VERSION 5.8 ;
BUSBITCHARS "[]" ;
DIVIDERCHAR "/" ;
UNITS
    DATABASE MICRONS 1000 ;
END UNITS

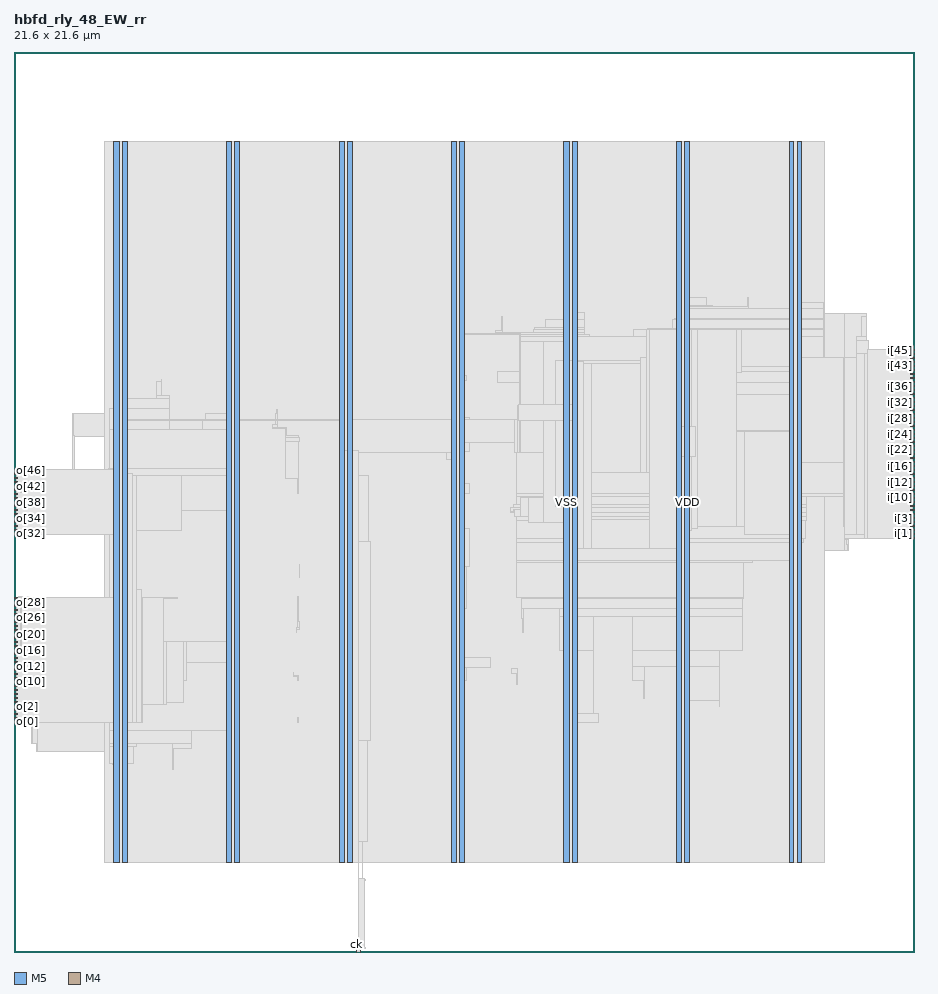
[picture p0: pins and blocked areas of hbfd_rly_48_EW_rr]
MACRO hbfd_rly_48_EW_rr
  FOREIGN hbfd_rly_48_EW_rr 0 0 ;
  CLASS BLOCK ;
  SIZE 21.6 BY 21.6 ;
  PIN ck
    DIRECTION INPUT ;
    USE SIGNAL ;
    PORT
      LAYER M5 ;
        RECT  8.208 0 8.232 0.084 ;
    END
  END ck
  PIN i[0]
    DIRECTION INPUT ;
    USE SIGNAL ;
    PORT
      LAYER M4 ;
        RECT  21.516 9.936 21.6 9.96 ;
    END
  END i[0]
  PIN i[10]
    DIRECTION INPUT ;
    USE SIGNAL ;
    PORT
      LAYER M4 ;
        RECT  21.516 10.896 21.6 10.92 ;
    END
  END i[10]
  PIN i[11]
    DIRECTION INPUT ;
    USE SIGNAL ;
    PORT
      LAYER M4 ;
        RECT  21.516 10.992 21.6 11.016 ;
    END
  END i[11]
  PIN i[12]
    DIRECTION INPUT ;
    USE SIGNAL ;
    PORT
      LAYER M4 ;
        RECT  21.516 11.088 21.6 11.112 ;
    END
  END i[12]
  PIN i[13]
    DIRECTION INPUT ;
    USE SIGNAL ;
    PORT
      LAYER M4 ;
        RECT  21.516 11.184 21.6 11.208 ;
    END
  END i[13]
  PIN i[14]
    DIRECTION INPUT ;
    USE SIGNAL ;
    PORT
      LAYER M4 ;
        RECT  21.516 11.28 21.6 11.304 ;
    END
  END i[14]
  PIN i[15]
    DIRECTION INPUT ;
    USE SIGNAL ;
    PORT
      LAYER M4 ;
        RECT  21.516 11.376 21.6 11.4 ;
    END
  END i[15]
  PIN i[16]
    DIRECTION INPUT ;
    USE SIGNAL ;
    PORT
      LAYER M4 ;
        RECT  21.516 11.472 21.6 11.496 ;
    END
  END i[16]
  PIN i[17]
    DIRECTION INPUT ;
    USE SIGNAL ;
    PORT
      LAYER M4 ;
        RECT  21.516 11.568 21.6 11.592 ;
    END
  END i[17]
  PIN i[18]
    DIRECTION INPUT ;
    USE SIGNAL ;
    PORT
      LAYER M4 ;
        RECT  21.516 11.664 21.6 11.688 ;
    END
  END i[18]
  PIN i[19]
    DIRECTION INPUT ;
    USE SIGNAL ;
    PORT
      LAYER M4 ;
        RECT  21.516 11.76 21.6 11.784 ;
    END
  END i[19]
  PIN i[1]
    DIRECTION INPUT ;
    USE SIGNAL ;
    PORT
      LAYER M4 ;
        RECT  21.516 10.032 21.6 10.056 ;
    END
  END i[1]
  PIN i[20]
    DIRECTION INPUT ;
    USE SIGNAL ;
    PORT
      LAYER M4 ;
        RECT  21.516 11.856 21.6 11.88 ;
    END
  END i[20]
  PIN i[21]
    DIRECTION INPUT ;
    USE SIGNAL ;
    PORT
      LAYER M4 ;
        RECT  21.516 11.952 21.6 11.976 ;
    END
  END i[21]
  PIN i[22]
    DIRECTION INPUT ;
    USE SIGNAL ;
    PORT
      LAYER M4 ;
        RECT  21.516 12.048 21.6 12.072 ;
    END
  END i[22]
  PIN i[23]
    DIRECTION INPUT ;
    USE SIGNAL ;
    PORT
      LAYER M4 ;
        RECT  21.516 12.144 21.6 12.168 ;
    END
  END i[23]
  PIN i[24]
    DIRECTION INPUT ;
    USE SIGNAL ;
    PORT
      LAYER M4 ;
        RECT  21.516 12.24 21.6 12.264 ;
    END
  END i[24]
  PIN i[25]
    DIRECTION INPUT ;
    USE SIGNAL ;
    PORT
      LAYER M4 ;
        RECT  21.516 12.336 21.6 12.36 ;
    END
  END i[25]
  PIN i[26]
    DIRECTION INPUT ;
    USE SIGNAL ;
    PORT
      LAYER M4 ;
        RECT  21.516 12.432 21.6 12.456 ;
    END
  END i[26]
  PIN i[27]
    DIRECTION INPUT ;
    USE SIGNAL ;
    PORT
      LAYER M4 ;
        RECT  21.516 12.528 21.6 12.552 ;
    END
  END i[27]
  PIN i[28]
    DIRECTION INPUT ;
    USE SIGNAL ;
    PORT
      LAYER M4 ;
        RECT  21.516 12.624 21.6 12.648 ;
    END
  END i[28]
  PIN i[29]
    DIRECTION INPUT ;
    USE SIGNAL ;
    PORT
      LAYER M4 ;
        RECT  21.516 12.72 21.6 12.744 ;
    END
  END i[29]
  PIN i[2]
    DIRECTION INPUT ;
    USE SIGNAL ;
    PORT
      LAYER M4 ;
        RECT  21.516 10.128 21.6 10.152 ;
    END
  END i[2]
  PIN i[30]
    DIRECTION INPUT ;
    USE SIGNAL ;
    PORT
      LAYER M4 ;
        RECT  21.516 12.816 21.6 12.84 ;
    END
  END i[30]
  PIN i[31]
    DIRECTION INPUT ;
    USE SIGNAL ;
    PORT
      LAYER M4 ;
        RECT  21.516 12.912 21.6 12.936 ;
    END
  END i[31]
  PIN i[32]
    DIRECTION INPUT ;
    USE SIGNAL ;
    PORT
      LAYER M4 ;
        RECT  21.516 13.008 21.6 13.032 ;
    END
  END i[32]
  PIN i[33]
    DIRECTION INPUT ;
    USE SIGNAL ;
    PORT
      LAYER M4 ;
        RECT  21.516 13.104 21.6 13.128 ;
    END
  END i[33]
  PIN i[34]
    DIRECTION INPUT ;
    USE SIGNAL ;
    PORT
      LAYER M4 ;
        RECT  21.516 13.2 21.6 13.224 ;
    END
  END i[34]
  PIN i[35]
    DIRECTION INPUT ;
    USE SIGNAL ;
    PORT
      LAYER M4 ;
        RECT  21.516 13.296 21.6 13.32 ;
    END
  END i[35]
  PIN i[36]
    DIRECTION INPUT ;
    USE SIGNAL ;
    PORT
      LAYER M4 ;
        RECT  21.516 13.392 21.6 13.416 ;
    END
  END i[36]
  PIN i[37]
    DIRECTION INPUT ;
    USE SIGNAL ;
    PORT
      LAYER M4 ;
        RECT  21.516 13.488 21.6 13.512 ;
    END
  END i[37]
  PIN i[38]
    DIRECTION INPUT ;
    USE SIGNAL ;
    PORT
      LAYER M4 ;
        RECT  21.516 13.584 21.6 13.608 ;
    END
  END i[38]
  PIN i[39]
    DIRECTION INPUT ;
    USE SIGNAL ;
    PORT
      LAYER M4 ;
        RECT  21.516 13.68 21.6 13.704 ;
    END
  END i[39]
  PIN i[3]
    DIRECTION INPUT ;
    USE SIGNAL ;
    PORT
      LAYER M4 ;
        RECT  21.516 10.224 21.6 10.248 ;
    END
  END i[3]
  PIN i[40]
    DIRECTION INPUT ;
    USE SIGNAL ;
    PORT
      LAYER M4 ;
        RECT  21.516 13.776 21.6 13.8 ;
    END
  END i[40]
  PIN i[41]
    DIRECTION INPUT ;
    USE SIGNAL ;
    PORT
      LAYER M4 ;
        RECT  21.516 13.872 21.6 13.896 ;
    END
  END i[41]
  PIN i[42]
    DIRECTION INPUT ;
    USE SIGNAL ;
    PORT
      LAYER M4 ;
        RECT  21.516 13.968 21.6 13.992 ;
    END
  END i[42]
  PIN i[43]
    DIRECTION INPUT ;
    USE SIGNAL ;
    PORT
      LAYER M4 ;
        RECT  21.516 14.064 21.6 14.088 ;
    END
  END i[43]
  PIN i[44]
    DIRECTION INPUT ;
    USE SIGNAL ;
    PORT
      LAYER M4 ;
        RECT  21.516 14.16 21.6 14.184 ;
    END
  END i[44]
  PIN i[45]
    DIRECTION INPUT ;
    USE SIGNAL ;
    PORT
      LAYER M4 ;
        RECT  21.516 14.256 21.6 14.28 ;
    END
  END i[45]
  PIN i[46]
    DIRECTION INPUT ;
    USE SIGNAL ;
    PORT
      LAYER M4 ;
        RECT  21.516 14.352 21.6 14.376 ;
    END
  END i[46]
  PIN i[47]
    DIRECTION INPUT ;
    USE SIGNAL ;
    PORT
      LAYER M4 ;
        RECT  21.516 14.448 21.6 14.472 ;
    END
  END i[47]
  PIN i[4]
    DIRECTION INPUT ;
    USE SIGNAL ;
    PORT
      LAYER M4 ;
        RECT  21.516 10.32 21.6 10.344 ;
    END
  END i[4]
  PIN i[5]
    DIRECTION INPUT ;
    USE SIGNAL ;
    PORT
      LAYER M4 ;
        RECT  21.516 10.416 21.6 10.44 ;
    END
  END i[5]
  PIN i[6]
    DIRECTION INPUT ;
    USE SIGNAL ;
    PORT
      LAYER M4 ;
        RECT  21.516 10.512 21.6 10.536 ;
    END
  END i[6]
  PIN i[7]
    DIRECTION INPUT ;
    USE SIGNAL ;
    PORT
      LAYER M4 ;
        RECT  21.516 10.608 21.6 10.632 ;
    END
  END i[7]
  PIN i[8]
    DIRECTION INPUT ;
    USE SIGNAL ;
    PORT
      LAYER M4 ;
        RECT  21.516 10.704 21.6 10.728 ;
    END
  END i[8]
  PIN i[9]
    DIRECTION INPUT ;
    USE SIGNAL ;
    PORT
      LAYER M4 ;
        RECT  21.516 10.8 21.6 10.824 ;
    END
  END i[9]
  PIN o[0]
    DIRECTION OUTPUT ;
    USE SIGNAL ;
    PORT
      LAYER M4 ;
        RECT  0 5.52 0.084 5.544 ;
    END
  END o[0]
  PIN o[10]
    DIRECTION OUTPUT ;
    USE SIGNAL ;
    PORT
      LAYER M4 ;
        RECT  0 6.48 0.084 6.504 ;
    END
  END o[10]
  PIN o[11]
    DIRECTION OUTPUT ;
    USE SIGNAL ;
    PORT
      LAYER M4 ;
        RECT  0 6.576 0.084 6.6 ;
    END
  END o[11]
  PIN o[12]
    DIRECTION OUTPUT ;
    USE SIGNAL ;
    PORT
      LAYER M4 ;
        RECT  0 6.672 0.084 6.696 ;
    END
  END o[12]
  PIN o[13]
    DIRECTION OUTPUT ;
    USE SIGNAL ;
    PORT
      LAYER M4 ;
        RECT  0 6.768 0.084 6.792 ;
    END
  END o[13]
  PIN o[14]
    DIRECTION OUTPUT ;
    USE SIGNAL ;
    PORT
      LAYER M4 ;
        RECT  0 6.864 0.084 6.888 ;
    END
  END o[14]
  PIN o[15]
    DIRECTION OUTPUT ;
    USE SIGNAL ;
    PORT
      LAYER M4 ;
        RECT  0 6.96 0.084 6.984 ;
    END
  END o[15]
  PIN o[16]
    DIRECTION OUTPUT ;
    USE SIGNAL ;
    PORT
      LAYER M4 ;
        RECT  0 7.056 0.084 7.08 ;
    END
  END o[16]
  PIN o[17]
    DIRECTION OUTPUT ;
    USE SIGNAL ;
    PORT
      LAYER M4 ;
        RECT  0 7.152 0.084 7.176 ;
    END
  END o[17]
  PIN o[18]
    DIRECTION OUTPUT ;
    USE SIGNAL ;
    PORT
      LAYER M4 ;
        RECT  0 7.248 0.084 7.272 ;
    END
  END o[18]
  PIN o[19]
    DIRECTION OUTPUT ;
    USE SIGNAL ;
    PORT
      LAYER M4 ;
        RECT  0 7.344 0.084 7.368 ;
    END
  END o[19]
  PIN o[1]
    DIRECTION OUTPUT ;
    USE SIGNAL ;
    PORT
      LAYER M4 ;
        RECT  0 5.616 0.084 5.64 ;
    END
  END o[1]
  PIN o[20]
    DIRECTION OUTPUT ;
    USE SIGNAL ;
    PORT
      LAYER M4 ;
        RECT  0 7.44 0.084 7.464 ;
    END
  END o[20]
  PIN o[21]
    DIRECTION OUTPUT ;
    USE SIGNAL ;
    PORT
      LAYER M4 ;
        RECT  0 7.536 0.084 7.56 ;
    END
  END o[21]
  PIN o[22]
    DIRECTION OUTPUT ;
    USE SIGNAL ;
    PORT
      LAYER M4 ;
        RECT  0 7.632 0.084 7.656 ;
    END
  END o[22]
  PIN o[23]
    DIRECTION OUTPUT ;
    USE SIGNAL ;
    PORT
      LAYER M4 ;
        RECT  0 7.728 0.084 7.752 ;
    END
  END o[23]
  PIN o[24]
    DIRECTION OUTPUT ;
    USE SIGNAL ;
    PORT
      LAYER M4 ;
        RECT  0 7.824 0.084 7.848 ;
    END
  END o[24]
  PIN o[25]
    DIRECTION OUTPUT ;
    USE SIGNAL ;
    PORT
      LAYER M4 ;
        RECT  0 7.92 0.084 7.944 ;
    END
  END o[25]
  PIN o[26]
    DIRECTION OUTPUT ;
    USE SIGNAL ;
    PORT
      LAYER M4 ;
        RECT  0 8.016 0.084 8.04 ;
    END
  END o[26]
  PIN o[27]
    DIRECTION OUTPUT ;
    USE SIGNAL ;
    PORT
      LAYER M4 ;
        RECT  0 8.112 0.084 8.136 ;
    END
  END o[27]
  PIN o[28]
    DIRECTION OUTPUT ;
    USE SIGNAL ;
    PORT
      LAYER M4 ;
        RECT  0 8.208 0.084 8.232 ;
    END
  END o[28]
  PIN o[29]
    DIRECTION OUTPUT ;
    USE SIGNAL ;
    PORT
      LAYER M4 ;
        RECT  0 8.304 0.084 8.328 ;
    END
  END o[29]
  PIN o[2]
    DIRECTION OUTPUT ;
    USE SIGNAL ;
    PORT
      LAYER M4 ;
        RECT  0 5.712 0.084 5.736 ;
    END
  END o[2]
  PIN o[30]
    DIRECTION OUTPUT ;
    USE SIGNAL ;
    PORT
      LAYER M4 ;
        RECT  0 8.4 0.084 8.424 ;
    END
  END o[30]
  PIN o[31]
    DIRECTION OUTPUT ;
    USE SIGNAL ;
    PORT
      LAYER M4 ;
        RECT  0 8.496 0.084 8.52 ;
    END
  END o[31]
  PIN o[32]
    DIRECTION OUTPUT ;
    USE SIGNAL ;
    PORT
      LAYER M4 ;
        RECT  0 10.032 0.084 10.056 ;
    END
  END o[32]
  PIN o[33]
    DIRECTION OUTPUT ;
    USE SIGNAL ;
    PORT
      LAYER M4 ;
        RECT  0 10.128 0.084 10.152 ;
    END
  END o[33]
  PIN o[34]
    DIRECTION OUTPUT ;
    USE SIGNAL ;
    PORT
      LAYER M4 ;
        RECT  0 10.224 0.084 10.248 ;
    END
  END o[34]
  PIN o[35]
    DIRECTION OUTPUT ;
    USE SIGNAL ;
    PORT
      LAYER M4 ;
        RECT  0 10.32 0.084 10.344 ;
    END
  END o[35]
  PIN o[36]
    DIRECTION OUTPUT ;
    USE SIGNAL ;
    PORT
      LAYER M4 ;
        RECT  0 10.416 0.084 10.44 ;
    END
  END o[36]
  PIN o[37]
    DIRECTION OUTPUT ;
    USE SIGNAL ;
    PORT
      LAYER M4 ;
        RECT  0 10.512 0.084 10.536 ;
    END
  END o[37]
  PIN o[38]
    DIRECTION OUTPUT ;
    USE SIGNAL ;
    PORT
      LAYER M4 ;
        RECT  0 10.608 0.084 10.632 ;
    END
  END o[38]
  PIN o[39]
    DIRECTION OUTPUT ;
    USE SIGNAL ;
    PORT
      LAYER M4 ;
        RECT  0 10.704 0.084 10.728 ;
    END
  END o[39]
  PIN o[3]
    DIRECTION OUTPUT ;
    USE SIGNAL ;
    PORT
      LAYER M4 ;
        RECT  0 5.808 0.084 5.832 ;
    END
  END o[3]
  PIN o[40]
    DIRECTION OUTPUT ;
    USE SIGNAL ;
    PORT
      LAYER M4 ;
        RECT  0 10.8 0.084 10.824 ;
    END
  END o[40]
  PIN o[41]
    DIRECTION OUTPUT ;
    USE SIGNAL ;
    PORT
      LAYER M4 ;
        RECT  0 10.896 0.084 10.92 ;
    END
  END o[41]
  PIN o[42]
    DIRECTION OUTPUT ;
    USE SIGNAL ;
    PORT
      LAYER M4 ;
        RECT  0 10.992 0.084 11.016 ;
    END
  END o[42]
  PIN o[43]
    DIRECTION OUTPUT ;
    USE SIGNAL ;
    PORT
      LAYER M4 ;
        RECT  0 11.088 0.084 11.112 ;
    END
  END o[43]
  PIN o[44]
    DIRECTION OUTPUT ;
    USE SIGNAL ;
    PORT
      LAYER M4 ;
        RECT  0 11.184 0.084 11.208 ;
    END
  END o[44]
  PIN o[45]
    DIRECTION OUTPUT ;
    USE SIGNAL ;
    PORT
      LAYER M4 ;
        RECT  0 11.28 0.084 11.304 ;
    END
  END o[45]
  PIN o[46]
    DIRECTION OUTPUT ;
    USE SIGNAL ;
    PORT
      LAYER M4 ;
        RECT  0 11.376 0.084 11.4 ;
    END
  END o[46]
  PIN o[47]
    DIRECTION OUTPUT ;
    USE SIGNAL ;
    PORT
      LAYER M4 ;
        RECT  0 11.472 0.084 11.496 ;
    END
  END o[47]
  PIN o[4]
    DIRECTION OUTPUT ;
    USE SIGNAL ;
    PORT
      LAYER M4 ;
        RECT  0 5.904 0.084 5.928 ;
    END
  END o[4]
  PIN o[5]
    DIRECTION OUTPUT ;
    USE SIGNAL ;
    PORT
      LAYER M4 ;
        RECT  0 6 0.084 6.024 ;
    END
  END o[5]
  PIN o[6]
    DIRECTION OUTPUT ;
    USE SIGNAL ;
    PORT
      LAYER M4 ;
        RECT  0 6.096 0.084 6.12 ;
    END
  END o[6]
  PIN o[7]
    DIRECTION OUTPUT ;
    USE SIGNAL ;
    PORT
      LAYER M4 ;
        RECT  0 6.192 0.084 6.216 ;
    END
  END o[7]
  PIN o[8]
    DIRECTION OUTPUT ;
    USE SIGNAL ;
    PORT
      LAYER M4 ;
        RECT  0 6.288 0.084 6.312 ;
    END
  END o[8]
  PIN o[9]
    DIRECTION OUTPUT ;
    USE SIGNAL ;
    PORT
      LAYER M4 ;
        RECT  0 6.384 0.084 6.408 ;
    END
  END o[9]
  PIN rs
    DIRECTION INPUT ;
    USE SIGNAL ;
    PORT
      LAYER M5 ;
        RECT  8.304 0 8.328 0.084 ;
    END
  END rs
  PIN rso
    DIRECTION OUTPUT ;
    USE SIGNAL ;
    PORT
      LAYER M4 ;
        RECT  0 11.568 0.084 11.592 ;
    END
  END rso
  PIN VDD
    DIRECTION INOUT ;
    USE POWER ;
    PORT
      LAYER M5 ;
        RECT  18.792 2.151 18.912 19.449 ;
        RECT  16.092 2.151 16.212 19.449 ;
        RECT  13.392 2.151 13.512 19.449 ;
        RECT  10.692 2.151 10.812 19.449 ;
        RECT  7.992 2.151 8.112 19.449 ;
        RECT  5.292 2.151 5.412 19.449 ;
        RECT  2.592 2.151 2.712 19.449 ;
    END
  END VDD
  PIN VSS
    DIRECTION INOUT ;
    USE GROUND ;
    PORT
      LAYER M5 ;
        RECT  18.6 2.137 18.72 19.463 ;
        RECT  15.9 2.137 16.02 19.463 ;
        RECT  13.2 2.137 13.32 19.463 ;
        RECT  10.5 2.137 10.62 19.463 ;
        RECT  7.8 2.137 7.92 19.463 ;
        RECT  5.1 2.137 5.22 19.463 ;
        RECT  2.4 2.137 2.52 19.463 ;
    END
  END VSS
  OBS
    LAYER RVTN ;
     RECT  2.16 2.16 19.44 2.295 ;
     RECT  2.16 2.565 19.44 2.835 ;
     RECT  2.16 3.105 19.44 3.375 ;
     RECT  2.16 3.645 19.44 3.915 ;
     RECT  2.16 4.185 19.44 4.455 ;
     RECT  2.16 4.725 19.44 4.995 ;
     RECT  2.16 5.265 19.44 5.535 ;
     RECT  2.16 5.805 19.44 6.075 ;
     RECT  2.16 6.345 19.44 6.615 ;
     RECT  2.16 6.885 19.44 7.155 ;
     RECT  2.16 7.425 19.44 7.695 ;
     RECT  2.16 7.965 19.44 8.235 ;
     RECT  2.16 8.505 19.44 8.775 ;
     RECT  2.16 9.045 19.44 9.315 ;
     RECT  2.16 9.585 19.44 9.855 ;
     RECT  2.16 10.125 19.44 10.395 ;
     RECT  2.16 10.665 19.44 10.935 ;
     RECT  2.16 11.205 19.44 11.475 ;
     RECT  2.16 11.745 19.44 12.015 ;
     RECT  2.16 12.285 19.44 12.555 ;
     RECT  2.16 12.825 19.44 13.095 ;
     RECT  2.16 13.365 19.44 13.635 ;
     RECT  2.16 13.905 19.44 14.175 ;
     RECT  2.16 14.445 19.44 14.715 ;
     RECT  2.16 14.985 19.44 15.255 ;
     RECT  2.16 15.525 19.44 15.795 ;
     RECT  2.16 16.065 19.44 16.335 ;
     RECT  2.16 16.605 19.44 16.875 ;
     RECT  2.16 17.145 19.44 17.415 ;
     RECT  2.16 17.685 19.44 17.955 ;
     RECT  2.16 18.225 19.44 18.495 ;
     RECT  2.16 18.765 19.44 19.035 ;
     RECT  2.16 19.305 19.44 19.44 ;
    LAYER RVTP ;
     RECT  2.16 2.295 19.44 2.565 ;
     RECT  2.16 2.835 19.44 3.105 ;
     RECT  2.16 3.375 19.44 3.645 ;
     RECT  2.16 3.915 19.44 4.185 ;
     RECT  2.16 4.455 19.44 4.725 ;
     RECT  2.16 4.995 19.44 5.265 ;
     RECT  2.16 5.535 19.44 5.805 ;
     RECT  2.16 6.075 19.44 6.345 ;
     RECT  2.16 6.615 19.44 6.885 ;
     RECT  2.16 7.155 19.44 7.425 ;
     RECT  2.16 7.695 19.44 7.965 ;
     RECT  2.16 8.235 19.44 8.505 ;
     RECT  2.16 8.775 19.44 9.045 ;
     RECT  2.16 9.315 19.44 9.585 ;
     RECT  2.16 9.855 19.44 10.125 ;
     RECT  2.16 10.395 19.44 10.665 ;
     RECT  2.16 10.935 19.44 11.205 ;
     RECT  2.16 11.475 19.44 11.745 ;
     RECT  2.16 12.015 19.44 12.285 ;
     RECT  2.16 12.555 19.44 12.825 ;
     RECT  2.16 13.095 19.44 13.365 ;
     RECT  2.16 13.635 19.44 13.905 ;
     RECT  2.16 14.175 19.44 14.445 ;
     RECT  2.16 14.715 19.44 14.985 ;
     RECT  2.16 15.255 19.44 15.525 ;
     RECT  2.16 15.795 19.44 16.065 ;
     RECT  2.16 16.335 19.44 16.605 ;
     RECT  2.16 16.875 19.44 17.145 ;
     RECT  2.16 17.415 19.44 17.685 ;
     RECT  2.16 17.955 19.44 18.225 ;
     RECT  2.16 18.495 19.44 18.765 ;
     RECT  2.16 19.035 19.44 19.305 ;
    LAYER M1 ;
     RECT  2.16 2.151 19.44 19.449 ;
    LAYER M2 ;
     RECT  0.103 7.704 0.139 7.722 ;
     RECT  0.103 8.478 0.139 8.496 ;
     RECT  0.139 7.704 0.347 8.496 ;
     RECT  0.347 7.776 0.419 7.794 ;
     RECT  0.211 5.616 0.427 5.634 ;
     RECT  0.427 5.004 0.499 5.634 ;
     RECT  0.499 5.004 0.535 5.832 ;
     RECT  1.399 12.906 1.435 12.924 ;
     RECT  0.535 4.806 2.16 6.174 ;
     RECT  1.435 12.366 2.16 12.924 ;
     RECT  2.16 2.151 19.44 19.449 ;
     RECT  19.44 9.63 19.931 15.318 ;
     RECT  19.931 9.63 20.039 13.086 ;
     RECT  20.039 10.098 20.255 13.086 ;
     RECT  20.255 10.098 20.399 12.276 ;
     RECT  20.399 10.098 20.435 11.736 ;
     RECT  20.255 13.068 20.435 13.086 ;
     RECT  20.435 10.368 20.471 10.998 ;
     RECT  19.931 14.148 20.471 15.318 ;
     RECT  20.471 10.368 20.507 10.926 ;
     RECT  20.471 14.148 20.507 14.67 ;
    LAYER M3 ;
     RECT  8.352 1.723 8.37 2.143 ;
     RECT  2.415 2.143 2.505 2.413 ;
     RECT  5.115 2.143 5.205 2.413 ;
     RECT  10.515 2.143 10.605 2.413 ;
     RECT  13.215 2.143 13.305 2.413 ;
     RECT  15.915 2.143 16.005 2.413 ;
     RECT  18.615 2.143 18.705 2.413 ;
     RECT  7.815 2.143 8.37 2.641 ;
     RECT  2.415 2.413 2.697 4.495 ;
     RECT  2.376 4.495 2.697 4.531 ;
     RECT  3.816 4.387 3.834 4.891 ;
     RECT  2.304 4.531 2.862 4.927 ;
     RECT  0.54 4.801 0.558 4.999 ;
     RECT  2.304 4.927 2.934 4.999 ;
     RECT  3.816 4.891 4.266 4.999 ;
     RECT  7.815 2.641 8.478 5.071 ;
     RECT  2.304 4.999 4.266 5.305 ;
     RECT  5.115 2.413 5.397 5.305 ;
     RECT  13.215 2.413 13.497 5.503 ;
     RECT  0.432 4.999 0.558 5.515 ;
     RECT  0.432 5.515 0.666 5.611 ;
     RECT  6.804 5.503 6.822 5.639 ;
     RECT  0.216 5.611 0.666 5.645 ;
     RECT  13.215 5.503 14.022 5.729 ;
     RECT  15.915 2.413 16.197 6.043 ;
     RECT  16.92 5.881 16.938 6.043 ;
     RECT  0.216 5.645 0.558 6.475 ;
     RECT  10.515 2.413 10.797 6.511 ;
     RECT  15.12 6.079 15.138 6.511 ;
     RECT  0.144 6.475 0.558 6.605 ;
     RECT  6.804 6.511 6.822 6.619 ;
     RECT  6.696 6.619 6.822 6.647 ;
     RECT  0.144 6.605 0.342 6.653 ;
     RECT  12.06 6.421 12.078 6.691 ;
     RECT  0.216 6.653 0.342 6.701 ;
     RECT  6.696 6.647 6.714 6.719 ;
     RECT  11.952 6.691 12.078 6.809 ;
     RECT  10.515 6.511 10.854 6.817 ;
     RECT  14.832 6.511 15.138 6.853 ;
     RECT  15.915 6.043 16.938 6.853 ;
     RECT  10.515 6.817 11.43 7.079 ;
     RECT  13.215 5.729 13.914 7.231 ;
     RECT  14.832 6.853 16.938 7.231 ;
     RECT  0.324 6.701 0.342 7.627 ;
     RECT  0.108 7.627 0.342 7.727 ;
     RECT  6.768 7.663 6.786 7.735 ;
     RECT  0.144 7.727 0.342 7.771 ;
     RECT  6.768 7.735 6.858 7.799 ;
     RECT  6.804 7.799 6.858 7.925 ;
     RECT  0.144 7.771 0.414 7.949 ;
     RECT  12.204 7.663 12.222 8.005 ;
     RECT  13.104 7.231 13.914 8.041 ;
     RECT  14.832 7.231 17.478 8.041 ;
     RECT  10.515 7.079 10.797 8.239 ;
     RECT  12.168 8.005 12.222 8.239 ;
     RECT  13.104 8.041 17.478 8.239 ;
     RECT  0.144 7.949 0.378 8.473 ;
     RECT  12.168 8.239 17.478 8.473 ;
     RECT  12.168 8.473 17.514 8.509 ;
     RECT  0.108 8.473 0.378 8.525 ;
     RECT  6.804 7.925 6.822 8.537 ;
     RECT  10.515 8.239 10.854 9.247 ;
     RECT  6.84 8.977 6.858 9.311 ;
     RECT  12.06 8.509 17.514 9.355 ;
     RECT  12.06 9.355 17.73 9.391 ;
     RECT  18.615 2.413 18.897 9.391 ;
     RECT  20.016 9.625 20.034 9.787 ;
     RECT  12.06 9.391 18.897 9.823 ;
     RECT  7.815 5.071 8.55 9.851 ;
     RECT  19.98 9.787 20.034 9.895 ;
     RECT  12.06 9.823 18.954 9.931 ;
     RECT  19.944 9.895 20.034 9.931 ;
     RECT  19.944 9.931 20.43 10.123 ;
     RECT  10.515 9.247 10.926 10.157 ;
     RECT  19.944 10.123 20.502 10.219 ;
     RECT  12.06 9.931 18.99 10.363 ;
     RECT  12.06 10.363 19.026 10.459 ;
     RECT  1.44 10.219 1.458 10.507 ;
     RECT  12.024 10.459 19.026 10.555 ;
     RECT  11.916 10.555 19.026 10.661 ;
     RECT  11.988 10.661 19.026 10.733 ;
     RECT  0.144 10.651 0.162 10.829 ;
     RECT  19.908 10.219 20.502 10.931 ;
     RECT  12.06 10.733 19.026 10.939 ;
     RECT  19.908 10.931 20.466 10.939 ;
     RECT  12.06 10.939 20.466 11.003 ;
     RECT  10.515 10.157 10.797 11.011 ;
     RECT  0.216 11.083 0.378 11.213 ;
     RECT  10.515 11.011 10.926 11.237 ;
     RECT  0.216 11.213 0.306 11.309 ;
     RECT  6.804 11.011 6.822 11.371 ;
     RECT  0.288 11.309 0.306 11.405 ;
     RECT  2.304 5.305 5.397 11.419 ;
     RECT  7.815 9.851 8.514 11.435 ;
     RECT  2.268 11.419 5.397 11.597 ;
     RECT  10.515 11.237 10.797 11.821 ;
     RECT  10.368 11.821 10.797 11.995 ;
     RECT  12.06 11.003 20.43 11.995 ;
     RECT  10.296 11.995 10.797 12.019 ;
     RECT  6.516 11.371 6.822 12.253 ;
     RECT  12.024 11.995 20.43 12.325 ;
     RECT  6.516 12.253 6.858 12.353 ;
     RECT  1.404 10.507 1.458 12.389 ;
     RECT  6.516 12.353 6.822 12.389 ;
     RECT  11.988 12.325 20.43 12.413 ;
     RECT  10.224 12.019 10.926 12.479 ;
     RECT  12.06 12.413 20.43 12.509 ;
     RECT  2.304 11.597 5.397 12.551 ;
     RECT  6.516 12.389 6.534 12.559 ;
     RECT  6.192 12.559 6.534 12.587 ;
     RECT  6.192 12.587 6.318 12.659 ;
     RECT  4.536 12.551 5.397 12.785 ;
     RECT  10.515 12.479 10.926 12.821 ;
     RECT  1.404 12.389 1.422 12.929 ;
     RECT  4.608 12.785 5.397 12.929 ;
     RECT  6.264 12.659 6.318 12.929 ;
     RECT  6.3 12.929 6.318 13.019 ;
     RECT  2.304 12.551 3.726 13.055 ;
     RECT  2.415 13.055 3.726 13.289 ;
     RECT  3.42 13.289 3.726 13.361 ;
     RECT  12.132 12.509 20.43 13.387 ;
     RECT  12.132 13.387 20.502 13.675 ;
     RECT  3.42 13.361 3.546 13.703 ;
     RECT  10.515 12.821 10.797 13.711 ;
     RECT  3.528 13.703 3.546 13.739 ;
     RECT  10.515 13.711 10.854 13.829 ;
     RECT  11.592 13.675 20.502 13.937 ;
     RECT  12.132 13.937 20.502 14.207 ;
     RECT  20.196 14.207 20.502 14.243 ;
     RECT  20.232 14.243 20.502 14.675 ;
     RECT  12.132 14.207 19.422 14.783 ;
     RECT  20.232 14.675 20.466 14.783 ;
     RECT  12.132 14.783 13.806 14.819 ;
     RECT  12.132 14.819 13.698 14.827 ;
     RECT  11.556 14.827 13.698 14.861 ;
     RECT  11.556 14.861 11.718 14.909 ;
     RECT  12.456 14.861 13.698 14.945 ;
     RECT  14.868 14.783 19.422 14.945 ;
     RECT  15.192 14.945 19.422 14.957 ;
     RECT  12.492 14.945 13.698 14.981 ;
     RECT  12.744 14.981 13.698 15.179 ;
     RECT  15.804 14.957 19.422 15.179 ;
     RECT  15.84 15.179 19.422 15.215 ;
     RECT  11.7 14.909 11.718 15.251 ;
     RECT  20.34 14.783 20.466 15.251 ;
     RECT  20.448 15.251 20.466 15.323 ;
     RECT  13.215 15.179 13.698 15.359 ;
     RECT  15.915 15.215 19.422 15.449 ;
     RECT  15.915 15.449 17.622 15.485 ;
     RECT  15.915 15.485 16.758 15.521 ;
     RECT  18.615 15.449 19.422 15.593 ;
     RECT  15.915 15.521 16.614 15.719 ;
     RECT  17.604 15.485 17.622 15.719 ;
     RECT  2.415 13.289 2.697 19.187 ;
     RECT  5.115 12.929 5.397 19.187 ;
     RECT  7.815 11.435 8.097 19.187 ;
     RECT  10.515 13.829 10.797 19.187 ;
     RECT  13.215 15.359 13.497 19.187 ;
     RECT  15.915 15.719 16.197 19.187 ;
     RECT  18.615 15.593 18.897 19.187 ;
     RECT  2.415 19.187 2.505 19.457 ;
     RECT  5.115 19.187 5.205 19.457 ;
     RECT  7.815 19.187 7.905 19.457 ;
     RECT  10.515 19.187 10.605 19.457 ;
     RECT  13.215 19.187 13.305 19.457 ;
     RECT  15.915 19.187 16.005 19.457 ;
     RECT  18.615 19.187 18.705 19.457 ;
    LAYER M4 ;
     RECT  0.06 5.52 2.408 8.52 ;
     RECT  0.06 10.032 2.408 11.592 ;
     RECT  2.408 2.148 2.512 19.452 ;
     RECT  2.512 2.418 2.704 19.182 ;
     RECT  2.704 5.52 2.839 11.496 ;
     RECT  2.839 5.52 2.945 11.448 ;
     RECT  2.945 5.52 3.053 8.712 ;
     RECT  3.053 5.52 3.089 8.52 ;
     RECT  3.089 5.952 3.593 8.52 ;
     RECT  3.593 5.952 3.665 7.464 ;
     RECT  3.593 8.496 3.917 8.52 ;
     RECT  2.945 10.128 4.025 11.448 ;
     RECT  3.665 6 4.061 7.464 ;
     RECT  4.061 6.528 4.133 7.464 ;
     RECT  4.133 6.96 5.108 7.464 ;
     RECT  4.025 10.608 5.108 11.448 ;
     RECT  2.704 12.768 5.108 12.792 ;
     RECT  5.108 2.148 5.212 19.452 ;
     RECT  5.212 2.418 5.404 19.182 ;
     RECT  5.404 12.768 7.808 12.792 ;
     RECT  7.808 2.148 7.912 19.452 ;
     RECT  7.912 2.148 8.104 19.182 ;
     RECT  8.101 0.096 8.291 0.216 ;
     RECT  8.291 0.096 8.435 0.12 ;
     RECT  8.341 1.728 8.435 1.752 ;
     RECT  8.104 12 10.508 12.792 ;
     RECT  10.508 2.148 10.612 19.452 ;
     RECT  10.612 2.418 10.804 19.182 ;
     RECT  11.905 10.56 11.977 10.584 ;
     RECT  11.977 10.56 12.013 10.632 ;
     RECT  10.804 12.24 12.013 12.792 ;
     RECT  12.013 12 12.085 12.792 ;
     RECT  12.085 12 12.121 13.128 ;
     RECT  10.804 14.832 12.121 14.856 ;
     RECT  12.013 10.464 12.157 10.632 ;
     RECT  12.121 12 12.161 14.856 ;
     RECT  12.157 10.464 12.337 10.92 ;
     RECT  12.337 10.32 12.697 10.92 ;
     RECT  12.161 12 12.697 14.664 ;
     RECT  12.697 10.32 13.208 14.664 ;
     RECT  13.208 2.148 13.312 19.452 ;
     RECT  13.312 2.418 13.504 19.182 ;
     RECT  13.504 9.696 13.673 14.184 ;
     RECT  13.673 9.696 13.853 14.136 ;
     RECT  13.853 11.52 15.037 14.136 ;
     RECT  15.037 11.52 15.181 14.28 ;
     RECT  13.853 9.696 15.253 10.392 ;
     RECT  15.181 11.52 15.253 14.952 ;
     RECT  15.253 9.696 15.908 14.952 ;
     RECT  15.908 2.148 16.012 19.452 ;
     RECT  16.012 2.418 16.204 19.182 ;
     RECT  16.204 10.128 16.265 14.952 ;
     RECT  16.265 10.176 16.409 14.952 ;
     RECT  16.409 10.224 17.345 14.952 ;
     RECT  17.345 13.92 17.453 14.952 ;
     RECT  17.345 10.224 17.521 12.504 ;
     RECT  17.521 10.032 18.608 12.504 ;
     RECT  17.453 14.064 18.608 14.952 ;
     RECT  18.608 2.148 18.712 19.452 ;
     RECT  18.712 2.418 18.904 19.182 ;
     RECT  18.904 11.76 19.897 14.28 ;
     RECT  19.897 10.224 19.933 14.28 ;
     RECT  19.933 10.032 20.221 14.28 ;
     RECT  20.221 10.032 20.401 14.376 ;
     RECT  20.401 9.936 20.473 14.376 ;
     RECT  20.473 9.936 21.564 14.472 ;
    LAYER M5 ;
     RECT  8.208 0.016 8.328 0.085 ;
     RECT  8.112 0.085 8.424 0.227 ;
     RECT  8.256 0.227 8.424 1.763 ;
     RECT  8.256 1.763 8.28 2.137 ;
     RECT  2.4 2.137 2.52 2.151 ;
     RECT  5.1 2.137 5.22 2.151 ;
     RECT  10.5 2.137 10.62 2.151 ;
     RECT  13.2 2.137 13.32 2.151 ;
     RECT  15.9 2.137 16.02 2.151 ;
     RECT  18.6 2.137 18.72 2.151 ;
     RECT  0.144 7.141 0.168 8.483 ;
     RECT  13.2 2.151 13.512 10.693 ;
     RECT  0.144 11.029 0.168 11.219 ;
     RECT  15.9 2.151 16.212 11.893 ;
     RECT  7.8 2.137 8.28 12.035 ;
     RECT  15.9 11.893 16.344 12.611 ;
     RECT  13.008 10.693 13.512 12.757 ;
     RECT  12.096 12.757 13.512 13.139 ;
     RECT  13.008 13.139 13.512 14.195 ;
     RECT  2.4 2.151 2.712 19.449 ;
     RECT  5.1 2.151 5.412 19.449 ;
     RECT  7.8 12.035 8.112 19.449 ;
     RECT  10.5 2.151 10.812 19.449 ;
     RECT  13.2 14.195 13.512 19.449 ;
     RECT  15.9 12.611 16.212 19.449 ;
     RECT  18.6 2.151 18.912 19.449 ;
     RECT  2.4 19.449 2.52 19.463 ;
     RECT  5.1 19.449 5.22 19.463 ;
     RECT  7.8 19.449 7.92 19.463 ;
     RECT  10.5 19.449 10.62 19.463 ;
     RECT  13.2 19.449 13.32 19.463 ;
     RECT  15.9 19.449 16.02 19.463 ;
     RECT  18.6 19.449 18.72 19.463 ;
  END
END hbfd_rly_48_EW_rr
END LIBRARY
